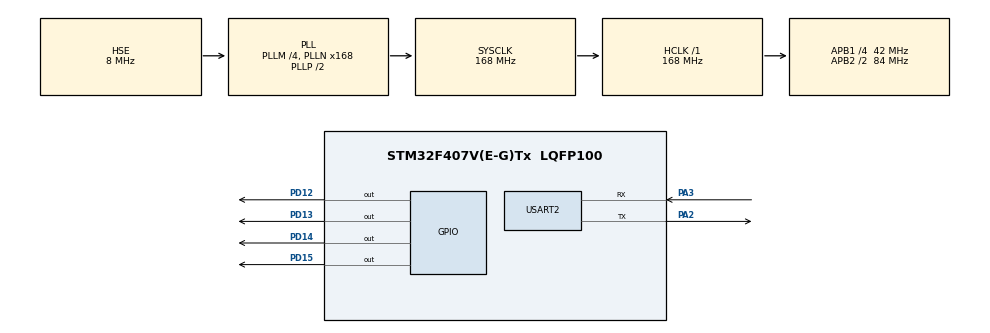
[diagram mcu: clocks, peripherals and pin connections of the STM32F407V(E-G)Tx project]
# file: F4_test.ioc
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Mcu.Family=STM32F4
Mcu.Name=STM32F407V(E-G)Tx
Mcu.Package=LQFP100
NVIC.PriorityGroup=NVIC_PRIORITYGROUP_4
NVIC.USART2_IRQn=true\:0\:0\:false\:false\:true\:true\:true
PA13.Mode=Serial_Wire
PA13.Signal=SYS_JTMS-SWDIO
PA14.Mode=Serial_Wire
PA14.Signal=SYS_JTCK-SWCLK
PA2.Mode=Asynchronous
PA2.Signal=USART2_TX
PA3.Mode=Asynchronous
PA3.Signal=USART2_RX
PD12.Signal=GPIO_Output
PD13.Signal=GPIO_Output
PD14.Signal=GPIO_Output
PD15.Signal=GPIO_Output
PH0-OSC_IN.Mode=HSE-External-Oscillator
PH0-OSC_IN.Signal=RCC_OSC_IN
PH1-OSC_OUT.Mode=HSE-External-Oscillator
PH1-OSC_OUT.Signal=RCC_OSC_OUT
ProjectManager.HeapSize=0x200
ProjectManager.StackSize=0x400
ProjectManager.TargetToolchain=STM32CubeIDE
RCC.48MHZClocksFreq_Value=84000000
RCC.AHBFreq_Value=168000000
RCC.APB1CLKDivider=RCC_HCLK_DIV4
RCC.APB1Freq_Value=42000000
RCC.APB1TimFreq_Value=84000000
RCC.APB2CLKDivider=RCC_HCLK_DIV2
RCC.APB2Freq_Value=84000000
RCC.APB2TimFreq_Value=168000000
RCC.CortexFreq_Value=168000000
RCC.HCLKFreq_Value=168000000
RCC.HSE_VALUE=8000000
RCC.HSI_VALUE=16000000
RCC.LSE_VALUE=32768
RCC.PLLM=4
RCC.PLLN=168
RCC.PLLSourceVirtual=RCC_PLLSOURCE_HSE
RCC.SYSCLKFreq_VALUE=168000000
RCC.SYSCLKSource=RCC_SYSCLKSOURCE_PLLCLK
RCC.VCOOutputFreq_Value=336000000
USART2.VirtualMode=VM_ASYNC
board=custom

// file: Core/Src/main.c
/* USER CODE BEGIN Header */
/**
  ******************************************************************************
  * @file           : main.c
  * @brief          : Main program body
  ******************************************************************************
  * @attention
  *
  * <h2><center>&copy; Copyright (c) 2022 STMicroelectronics.
  * All rights reserved.</center></h2>
  *
  * This software component is licensed by ST under BSD 3-Clause license,
  * the "License"; You may not use this file except in compliance with the
  * License. You may obtain a copy of the License at:
  *                        opensource.org/licenses/BSD-3-Clause
  *
  ******************************************************************************
  */
/* USER CODE END Header */

#include "main.h"

/* USER CODE BEGIN Includes */
#include "UartRingbuffer.h"
/* USER CODE END Includes */

UART_HandleTypeDef huart2;

void SystemClock_Config(void);
static void MX_GPIO_Init(void);
static void MX_USART2_UART_Init(void);

/* USER CODE BEGIN 0 */
uint8_t dem=0;
char *pump1="a0x\r\n";
char *pump2="b2x\r\n";
char *pump3="c4x\r\n";
char *pump4="d6x\r\n";
void HAL_GPIO_EXTI_Callback(uint16_t GPIO_Pin){
//	if(GPIO_Pin==GPIO_PIN_0){
//		if(check==0){
//			  HAL_GPIO_WritePin(GPIOD, GPIO_PIN_12, 1);
//			  check=1;
//		}else{
//		HAL_GPIO_WritePin(GPIOD, GPIO_PIN_12, 0);
//		check=0;
//		}
//		dem++;
//		for(int x=500000;x>0;x--);
//		__HAL_GPIO_EXTI_CLEAR_IT(GPIO_PIN_0);
//		HAL_NVIC_ClearPendingIRQ(EXTI0_IRQn);
//	}
switch(GPIO_Pin)
{
case GPIO_PIN_7:
{   if(pump1=="a0x\r\n"){
	Uart_sendstring("a1x\r\n");
			}else{
				Uart_sendstring("a0x\r\n");
			}
	for(int i=0;i<1000000;i++);
	int i=0;
	while(!HAL_GPIO_ReadPin(GPIOA,GPIO_PIN_7)&(i<1000000))
	{
		i++;
	}
	for(int i=0;i<1000000;i++);
	EXTI->PR|=GPIO_PIN_7;
	break;
}
case GPIO_PIN_8:
{   if(pump2=="b2x\r\n"){
	Uart_sendstring("b3x\r\n");
			}else{
				Uart_sendstring("b2x\r\n");
			}

	for(int i=0;i<1000000;i++);
	int i=0;
	while(!HAL_GPIO_ReadPin(GPIOA,GPIO_PIN_8)&(i<1000000))
	{
		i++;
	}
	for(int i=0;i<1000000;i++);
	EXTI->PR|=GPIO_PIN_8;
	break;
}
case GPIO_PIN_9:
{   if(pump3=="c4x\r\n"){
	Uart_sendstring("c5x\r\n");
			}else{
				Uart_sendstring("c4x\r\n");
			}

	for(int i=0;i<1000000;i++);
	int i=0;
	while(!HAL_GPIO_ReadPin(GPIOE,GPIO_PIN_9)&(i<1000000))
	{
		i++;
	}
	for(int i=0;i<1000000;i++);
	EXTI->PR|=GPIO_PIN_9;
	break;
}
case GPIO_PIN_10:
{   if(pump4=="d6x\r\n"){
	Uart_sendstring("d7x\r\n");
			}else{
				Uart_sendstring("d6x\r\n");
			}

	for(int i=0;i<1000000;i++);
	int i=0;
	while(!HAL_GPIO_ReadPin(GPIOE,GPIO_PIN_10)&(i<1000000))
	{
		i++;
	}
	for(int i=0;i<1000000;i++);
	EXTI->PR|=GPIO_PIN_10;
	break;
}
}
}
/* USER CODE END 0 */

int main(void)
{

  /* MCU Configuration--------------------------------------------------------*/

  /* Reset of all peripherals, Initializes the Flash interface and the Systick. */
  HAL_Init();

  /* Configure the system clock */
  SystemClock_Config();

  /* Initialize all configured peripherals */
  MX_GPIO_Init();
  MX_USART2_UART_Init();
  /* USER CODE BEGIN 2 */
Ringbuf_init();
  /* USER CODE END 2 */

  /* Infinite loop */
  while (1)
  {

    /* USER CODE BEGIN 3 */

	  if (IsDataAvailable()){
		  int data= Uart_read();
//		  Uart_write(data);
		  if(So_sanh("1\r\n")){
		  	  HAL_GPIO_WritePin(GPIOD, GPIO_PIN_12, 1);
		  	HAL_GPIO_WritePin(GPIOB, GPIO_PIN_4, 1);
		  	pump1="a1x\r\n";
		  	 }else if(So_sanh("2\r\n")){
		  	 HAL_GPIO_WritePin(GPIOD, GPIO_PIN_12, 0);
		  	 HAL_GPIO_WritePin(GPIOB, GPIO_PIN_4, 0);
		  	pump1="a0x\r\n";
		  	 }

		  if(So_sanh("3\r\n")){
			  HAL_GPIO_WritePin(GPIOD, GPIO_PIN_13, 1);
			  HAL_GPIO_WritePin(GPIOB, GPIO_PIN_5, 1);
			  pump2="b3x\r\n";
			  }else if(So_sanh("4\r\n")){
			   HAL_GPIO_WritePin(GPIOD, GPIO_PIN_13, 0);
			  	 HAL_GPIO_WritePin(GPIOB, GPIO_PIN_5, 0);
			  	pump2="b2x\r\n";
			  }
		  if(So_sanh("5\r\n")){
		  			  HAL_GPIO_WritePin(GPIOD, GPIO_PIN_14, 1);
		  			HAL_GPIO_WritePin(GPIOB, GPIO_PIN_6, 1);
		  			pump3="c5x\r\n";
		  			  }else if(So_sanh("6\r\n")){
		  			   HAL_GPIO_WritePin(GPIOD, GPIO_PIN_14, 0);
		  		  	 HAL_GPIO_WritePin(GPIOB, GPIO_PIN_6, 0);
		  		  	pump3="c4x\r\n";
		  			  }
		  if(So_sanh("7\r\n")){
		  			  HAL_GPIO_WritePin(GPIOD, GPIO_PIN_15, 1);
		  			HAL_GPIO_WritePin(GPIOB, GPIO_PIN_7, 1);
		  			pump4="d7x\r\n";
		  			  }else if(So_sanh("8\r\n")){
		  			   HAL_GPIO_WritePin(GPIOD, GPIO_PIN_15, 0);
		  		  	 HAL_GPIO_WritePin(GPIOB, GPIO_PIN_7, 0);
		  		  	pump4="d6x\r\n";
		  			  }

          }
//	         char check1[10];
//             itoa(check,check1,10);
//        	 strcat(check1,"x\r\n");
//        	 Uart_sendstring(pump1);
//        	 Uart_sendstring(pump2);
//        	 Uart_sendstring(pump3);
//        	 Uart_sendstring(pump4);
 }
  /* USER CODE END 3 */
}

void SystemClock_Config(void)
{
  RCC_OscInitTypeDef RCC_OscInitStruct = {0};
  RCC_ClkInitTypeDef RCC_ClkInitStruct = {0};

  /** Configure the main internal regulator output voltage
  */
  __HAL_RCC_PWR_CLK_ENABLE();
  __HAL_PWR_VOLTAGESCALING_CONFIG(PWR_REGULATOR_VOLTAGE_SCALE1);
  /** Initializes the CPU, AHB and APB busses clocks
  */
  RCC_OscInitStruct.OscillatorType = RCC_OSCILLATORTYPE_HSE;
  RCC_OscInitStruct.HSEState = RCC_HSE_ON;
  RCC_OscInitStruct.PLL.PLLState = RCC_PLL_ON;
  RCC_OscInitStruct.PLL.PLLSource = RCC_PLLSOURCE_HSE;
  RCC_OscInitStruct.PLL.PLLM = 4;
  RCC_OscInitStruct.PLL.PLLN = 168;
  RCC_OscInitStruct.PLL.PLLP = RCC_PLLP_DIV2;
  RCC_OscInitStruct.PLL.PLLQ = 4;
  if (HAL_RCC_OscConfig(&RCC_OscInitStruct) != HAL_OK)
  {
    Error_Handler();
  }
  /** Initializes the CPU, AHB and APB busses clocks
  */
  RCC_ClkInitStruct.ClockType = RCC_CLOCKTYPE_HCLK|RCC_CLOCKTYPE_SYSCLK
                              |RCC_CLOCKTYPE_PCLK1|RCC_CLOCKTYPE_PCLK2;
  RCC_ClkInitStruct.SYSCLKSource = RCC_SYSCLKSOURCE_PLLCLK;
  RCC_ClkInitStruct.AHBCLKDivider = RCC_SYSCLK_DIV1;
  RCC_ClkInitStruct.APB1CLKDivider = RCC_HCLK_DIV4;
  RCC_ClkInitStruct.APB2CLKDivider = RCC_HCLK_DIV2;

  if (HAL_RCC_ClockConfig(&RCC_ClkInitStruct, FLASH_LATENCY_5) != HAL_OK)
  {
    Error_Handler();
  }
}

static void MX_USART2_UART_Init(void)
{

  huart2.Instance = USART2;
  huart2.Init.BaudRate = 115200;
  huart2.Init.WordLength = UART_WORDLENGTH_8B;
  huart2.Init.StopBits = UART_STOPBITS_1;
  huart2.Init.Parity = UART_PARITY_NONE;
  huart2.Init.Mode = UART_MODE_TX_RX;
  huart2.Init.HwFlowCtl = UART_HWCONTROL_NONE;
  huart2.Init.OverSampling = UART_OVERSAMPLING_16;
  if (HAL_UART_Init(&huart2) != HAL_OK)
  {
    Error_Handler();
  }

}

static void MX_GPIO_Init(void)
{
  GPIO_InitTypeDef GPIO_InitStruct = {0};

  /* GPIO Ports Clock Enable */
  __HAL_RCC_GPIOH_CLK_ENABLE();
  __HAL_RCC_GPIOA_CLK_ENABLE();
  __HAL_RCC_GPIOE_CLK_ENABLE();
  __HAL_RCC_GPIOD_CLK_ENABLE();
  __HAL_RCC_GPIOB_CLK_ENABLE();

  /*Configure GPIO pin Output Level */
  HAL_GPIO_WritePin(GPIOD, GPIO_PIN_12|GPIO_PIN_13|GPIO_PIN_14|GPIO_PIN_15, GPIO_PIN_RESET);

  /*Configure GPIO pin Output Level */
  HAL_GPIO_WritePin(GPIOB, GPIO_PIN_4|GPIO_PIN_5|GPIO_PIN_6|GPIO_PIN_7, GPIO_PIN_RESET);

  /*Configure GPIO pin : PA0 */
  GPIO_InitStruct.Pin = GPIO_PIN_0;
  GPIO_InitStruct.Mode = GPIO_MODE_IT_RISING;
  GPIO_InitStruct.Pull = GPIO_NOPULL;
  HAL_GPIO_Init(GPIOA, &GPIO_InitStruct);

  /*Configure GPIO pins : PE7 PE8 PE9 PE10 */
  GPIO_InitStruct.Pin = GPIO_PIN_7|GPIO_PIN_8|GPIO_PIN_9|GPIO_PIN_10;
  GPIO_InitStruct.Mode = GPIO_MODE_IT_RISING;
  GPIO_InitStruct.Pull = GPIO_NOPULL;
  HAL_GPIO_Init(GPIOE, &GPIO_InitStruct);

  /*Configure GPIO pins : PD12 PD13 PD14 PD15 */
  GPIO_InitStruct.Pin = GPIO_PIN_12|GPIO_PIN_13|GPIO_PIN_14|GPIO_PIN_15;
  GPIO_InitStruct.Mode = GPIO_MODE_OUTPUT_PP;
  GPIO_InitStruct.Pull = GPIO_NOPULL;
  GPIO_InitStruct.Speed = GPIO_SPEED_FREQ_LOW;
  HAL_GPIO_Init(GPIOD, &GPIO_InitStruct);

  /*Configure GPIO pins : PB4 PB5 PB6 PB7 */
  GPIO_InitStruct.Pin = GPIO_PIN_4|GPIO_PIN_5|GPIO_PIN_6|GPIO_PIN_7;
  GPIO_InitStruct.Mode = GPIO_MODE_OUTPUT_PP;
  GPIO_InitStruct.Pull = GPIO_NOPULL;
  GPIO_InitStruct.Speed = GPIO_SPEED_FREQ_LOW;
  HAL_GPIO_Init(GPIOB, &GPIO_InitStruct);

  /* EXTI interrupt init*/
  HAL_NVIC_SetPriority(EXTI0_IRQn, 0, 0);
  HAL_NVIC_EnableIRQ(EXTI0_IRQn);

  HAL_NVIC_SetPriority(EXTI9_5_IRQn, 0, 0);
  HAL_NVIC_EnableIRQ(EXTI9_5_IRQn);

  HAL_NVIC_SetPriority(EXTI15_10_IRQn, 0, 0);
  HAL_NVIC_EnableIRQ(EXTI15_10_IRQn);

}

void Error_Handler(void)
{
}

/************************ (C) COPYRIGHT STMicroelectronics *****END OF FILE****/
